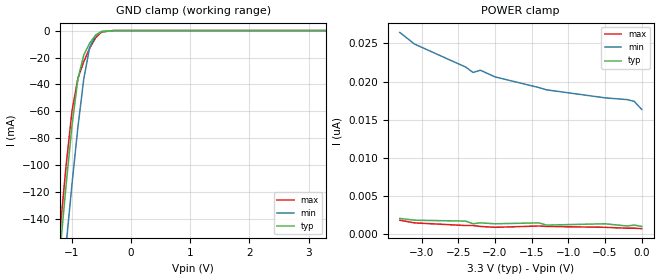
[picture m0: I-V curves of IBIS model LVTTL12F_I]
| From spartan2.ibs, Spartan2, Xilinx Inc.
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|   Model LVTTL12F_I
[Model]   LVTTL12F_I
Model_type   Input
Polarity   Non-Inverting
Vinl =   0.800V
Vinh =   2.000V
C_comp   6.5000pF   5.0000pF   8.0000pF
[Temperature Range]   27.0000   100.0000   0.000
[Voltage Range]   3.3000V   3.0000V   3.6000V
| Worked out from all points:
|   GND clamp passes 1 mA (typ) near -0.51 V on its own axis
[GND_clamp]
| voltage   I(typ)   I(min)   I(max)
-3.3V     -1.286A    -1.273A    -1.29A
-1.3V     -213.2mA   -255.1mA   -198mA
-1.2V     -163mA     -206.8mA   -147.7mA
-1.1V     -114.8mA   -159.6mA   -100.3mA
-1V       -70.57mA   -114.1mA   -59.86mA
-900mV    -35.79mA   -71.75mA   -35.46mA
-800mV    -18.04mA   -35.69mA   -22.98mA
-700mV    -9.256mA   -12.38mA   -13.06mA
-600mV    -3.388mA   -3.468mA   -5.299mA
-500mV    -637.4uA   -792.4uA   -1.07mA
-300mV    -3.973uA   -15.32uA   -4.185uA
3.3V      1.106nA    17.64nA    698.5pA
[POWER_clamp]
| voltage   I(typ)   I(min)   I(max)
-3.3V     2.095nA    26.43nA    1.863nA
-3.1V     1.863nA    24.91nA    1.513nA
-2.4V     1.746nA    21.89nA    1.164nA
-2.3V     1.397nA    21.19nA    1.164nA
-2.2V     1.513nA    21.48nA    1.048nA
-2V       1.397nA    20.61nA    931.3pA
-1.4V     1.513nA    19.21nA    1.106nA
-1.3V     1.222nA    18.92nA    1.048nA
-500mV    1.397nA    17.87nA    931.3pA
-200mV    1.106nA    17.64nA    814.9pA
-100mV    1.222nA    17.4nA     814.9pA
0V        1.048nA    16.36nA    756.7pA
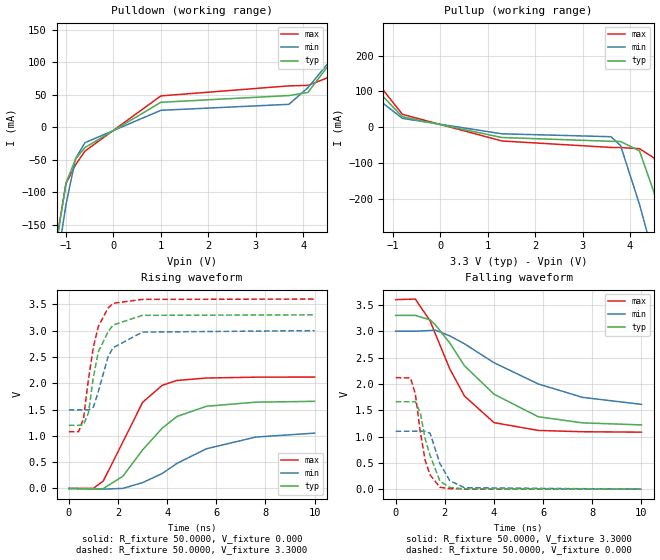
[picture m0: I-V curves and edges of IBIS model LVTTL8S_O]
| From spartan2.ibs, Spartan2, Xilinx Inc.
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|   Model LVTTL8S_O
[Model]   LVTTL8S_O
Model_type   Output
Polarity   Non-Inverting
Vmeas =   1.4000V
Cref =  35.0000pF
Rref =   1.0000M
Vref =  0.000V
C_comp   6.5000pF   5.0000pF   8.0000pF
[Temperature Range]   27.0000   100.0000   0.000
[Voltage Range]   3.3000V   3.0000V   3.6000V
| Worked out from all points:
|   slope of the pulldown table from 0 to 0.495 V, typ, clamps not added: 21.7 ohm
|   slope of the pullup table from 0 to 0.495 V, typ, clamps not added: 37.4 ohm
|   rising waveform, R_fixture 50.0000, V_fixture 0.000: 20-80 % time 1.89ns typ, 2.74ns min, 1.37ns max; typ from 0 V to 1.66 V
|   rising waveform, R_fixture 50.0000, V_fixture 3.3000: 20-80 % time 637ps typ, 679ps min, 554ps max; typ from 1.2 V to 3.3 V
|   falling waveform, R_fixture 50.0000, V_fixture 3.3000: 20-80 % time 2.49ns typ, 3.61ns min, 1.68ns max; typ from 3.3 V to 1.22 V
|   falling waveform, R_fixture 50.0000, V_fixture 0.000: 20-80 % time 547ps typ, 572ps min, 457ps max; typ from 1.66 V to 0 V
[Pulldown]
| voltage   I(typ)   I(min)   I(max)
-3.3V     -1.287A    -1.273A    -1.29A
-1.5V     -319.2mA   -355mA     -306.2mA
-1V       -85.7mA    -119mA     -86.53mA
-800mV    -49.26mA   -48.62mA   -58.07mA
-600mV    -31.33mA   -23.87mA   -36.76mA
1V        38.23mA    25.9mA     48.06mA
3.7V      48.63mA    35.12mA    63.51mA
4.1V      53.36mA    60.68mA    64.22mA
4.5V      91.81mA    96.06mA    75.48mA
4.9V      143.3mA    135.7mA    130.9mA
5.1V      170.4mA    156.5mA    163.1mA
6.6V      374.6mA    313mA      411.1mA
[Pullup]
| voltage   I(typ)   I(min)   I(max)
-3.3V     377.1mA    289.5mA    456.1mA
-2.5V     265.1mA    201.1mA    320.9mA
-800mV    29.02mA    24.47mA    35.82mA
1.3V      -28.95mA   -18.62mA   -38.67mA
3.6V      -39.57mA   -26.75mA   -56.67mA
3.8V      -40.09mA   -51.43mA   -57.06mA
4.2V      -66.46mA   -216mA     -60.14mA
4.5V      -180.3mA   -362.2mA   -85.65mA
4.7V      -279.8mA   -462.2mA   -132.6mA
4.9V      -383.6mA   -563.2mA   -223.6mA
5.1V      -489.4mA   -665mA     -325.3mA
6.6V      -1.3A      -1.436A    -1.143A
[Ramp]
| variable   typ   min   max
dV/dt_r   0.9936/1.9579n   0.6312/2.7392n   1.2702/1.3857n
dV/dt_f   1.2474/2.5568n   0.8334/3.5562n   1.5102/1.6863n
R_load = 50.0000
[Rising Waveform]
R_fixture = 50.0000
V_fixture = 0.000
| time   V(typ)   V(min)   V(max)
0s        0V         0V         0V
1ns       -12.71mV   -3.826mV   2.356mV
1.4ns     -2.362mV   -12.82mV   141.4mV
2.2ns     233.3mV    2.066mV    883.2mV
3ns       732mV      110.9mV    1.636V
3.8ns     1.147V     284.8mV    1.961V
4.4ns     1.368V     476.9mV    2.052V
5.6ns     1.562V     755.2mV    2.099V
7.6ns     1.64V      976.6mV    2.115V
10ns      1.656V     1.052V     2.117V
[Rising Waveform]
R_fixture = 50.0000
V_fixture = 3.3000
V_fixture_min = 3.0000
V_fixture_max = 3.6000
| time   V(typ)   V(min)   V(max)
0s        1.2V       1.493V     1.079V
400ps     1.2V       1.493V     1.08V
600ps     1.212V     1.493V     1.336V
800ps     1.438V     1.493V     2.078V
1ns       2.116V     1.547V     2.688V
1.2ns     2.596V     1.841V     3.076V
1.6ns     2.979V     2.508V     3.432V
1.8ns     3.106V     2.674V     3.518V
3ns       3.29V      2.972V     3.593V
10ns      3.299V     2.999V     3.599V
[Falling Waveform]
R_fixture = 50.0000
V_fixture = 3.3000
V_fixture_min = 3.0000
V_fixture_max = 3.6000
| time   V(typ)   V(min)   V(max)
0s        3.3V       3V         3.6V
800ps     3.3V       3V         3.611V
1.4ns     3.217V     3.014V     3.196V
1.6ns     3.129V     3.022V     2.966V
2.2ns     2.777V     2.912V     2.286V
2.8ns     2.343V     2.761V     1.768V
4ns       1.804V     2.402V     1.264V
5.8ns     1.376V     1.999V     1.116V
7.6ns     1.26V      1.744V     1.091V
10ns      1.221V     1.611V     1.083V
[Falling Waveform]
R_fixture = 50.0000
V_fixture = 0.000
| time   V(typ)   V(min)   V(max)
0s        1.661V     1.1V       2.118V
600ps     1.661V     1.1V       2.113V
800ps     1.662V     1.101V     1.809V
1ns       1.449V     1.101V     1.092V
1.2ns     955.3mV    1.101V     547.3mV
1.4ns     642.9mV    1.06V      270.2mV
1.8ns     151.3mV    486.3mV    36.26mV
2.2ns     33.33mV    161.3mV    10.3mV
2.8ns     6.159mV    27.53mV    3.684mV
10ns      338.1uV    436.9uV    299.4uV
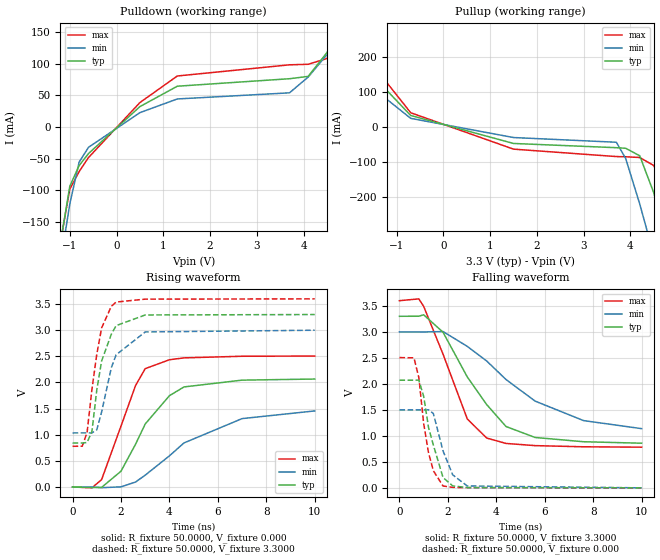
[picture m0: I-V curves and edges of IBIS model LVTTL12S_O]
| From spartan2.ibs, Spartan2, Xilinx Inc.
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|   Model LVTTL12S_O
[Model]   LVTTL12S_O
Model_type   Output
Polarity   Non-Inverting
Vmeas =   1.4000V
Cref =  35.0000pF
Rref =   1.0000M
Vref =  0.000V
C_comp   6.5000pF   5.0000pF   8.0000pF
[Temperature Range]   27.0000   100.0000   0.000
[Voltage Range]   3.3000V   3.0000V   3.6000V
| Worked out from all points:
|   slope of the pulldown table from 0 to 0.495 V, typ, clamps not added: 15.4 ohm
|   slope of the pullup table from 0 to 0.495 V, typ, clamps not added: 25.2 ohm
|   rising waveform, R_fixture 50.0000, V_fixture 0.000: 20-80 % time 1.65ns typ, 2.77ns min, 1.11ns max; typ from 0 V to 2.06 V
|   rising waveform, R_fixture 50.0000, V_fixture 3.3000: 20-80 % time 638ps typ, 706ps min, 524ps max; typ from 0.84 V to 3.3 V
|   falling waveform, R_fixture 50.0000, V_fixture 3.3000: 20-80 % time 2.01ns typ, 3.32ns min, 1.31ns max; typ from 3.3 V to 0.859 V
|   falling waveform, R_fixture 50.0000, V_fixture 0.000: 20-80 % time 589ps typ, 618ps min, 473ps max; typ from 2.07 V to 0 V
[Pulldown]
| voltage   I(typ)   I(min)   I(max)
-3.3V     -1.281A    -1.27A     -1.284A
-1.5V     -318.9mA   -354.1mA   -306.4mA
-1V       -93.51mA   -121.5mA   -98.08mA
-800mV    -60.84mA   -55.35mA   -70.38mA
-600mV    -41.86mA   -32.01mA   -48.2mA
500mV     32.35mA    22.81mA    38.75mA
1.3V      64.57mA    44.42mA    80.71mA
3.7V      76.41mA    54.11mA    98.37mA
4.1V      80.11mA    79.08mA    99.25mA
4.5V      117.6mA    114.4mA    108.3mA
4.9V      168.6mA    153.8mA    162.6mA
6.6V      399mA      330.4mA    441.4mA
[Pullup]
| voltage   I(typ)   I(min)   I(max)
-3.3V     401.3mA    308.2mA    484mA
-2.9V     344.8mA    263.9mA    415.5mA
-2.5V     286.5mA    217.5mA    345.7mA
-700mV    33.24mA    24.98mA    41.08mA
1.5V      -47.01mA   -30.01mA   -63.27mA
3.7V      -59.11mA   -43.53mA   -84.54mA
3.9V      -60.79mA   -90.24mA   -85.1mA
4.2V      -82.34mA   -220.4mA   -87.26mA
4.5V      -188.3mA   -366.3mA   -110.2mA
4.9V      -390.3mA   -567.2mA   -235.3mA
5.1V      -496mA     -668.9mA   -335.5mA
6.6V      -1.307A    -1.44A     -1.153A
[Ramp]
| variable   typ   min   max
dV/dt_r   1.2390/1.6423n   0.8730/2.7720n   1.5030/1.0990n
dV/dt_f   1.4647/2.0141n   1.1166/3.2951n   1.6905/1.3442n
R_load = 50.0000
[Rising Waveform]
R_fixture = 50.0000
V_fixture = 0.000
| time   V(typ)   V(min)   V(max)
0s        0V         0V         0V
800ps     -11.64mV   901.8uV    -16.88mV
1.2ns     -7.903mV   -14.23mV   141.6mV
2ns       301.5mV    2.076mV    1.165V
2.6ns     817mV      94.13mV    1.94V
3ns       1.205V     226.1mV    2.264V
4ns       1.747V     595.7mV    2.434V
4.6ns     1.914V     842.5mV    2.47V
7ns       2.044V     1.308V     2.501V
10ns      2.065V     1.455V     2.505V
[Rising Waveform]
R_fixture = 50.0000
V_fixture = 3.3000
V_fixture_min = 3.0000
V_fixture_max = 3.6000
| time   V(typ)   V(min)   V(max)
0s        840.3mV    1.034V     778.4mV
400ps     840.8mV    1.034V     779.6mV
600ps     850.7mV    1.034V     1.043V
800ps     1.063V     1.034V     1.867V
1ns       1.853V     1.094V     2.54V
1.2ns     2.411V     1.435V     3.043V
1.6ns     2.922V     2.281V     3.457V
1.8ns     3.087V     2.53V      3.538V
3ns       3.291V     2.966V     3.594V
10ns      3.299V     2.999V     3.599V
[Falling Waveform]
R_fixture = 50.0000
V_fixture = 3.3000
V_fixture_min = 3.0000
V_fixture_max = 3.6000
| time   V(typ)   V(min)   V(max)
0s        3.3V       3V         3.6V
800ps     3.301V     3V         3.635V
1ns       3.329V     2.999V     3.491V
1.8ns     2.993V     3.006V     2.571V
2.8ns     2.135V     2.722V     1.327V
3.6ns     1.603V     2.441V     958.1mV
4.4ns     1.18V      2.084V     854.7mV
5.6ns     969.4mV    1.669V     812.4mV
7.6ns     887.2mV    1.294V     790mV
10ns      858.8mV    1.139V     782.5mV
[Falling Waveform]
R_fixture = 50.0000
V_fixture = 0.000
| time   V(typ)   V(min)   V(max)
0s        2.07V      1.5V       2.506V
600ps     2.07V      1.5V       2.501V
800ps     2.072V     1.5V       2.126V
1ns       1.762V     1.5V       1.24V
1.2ns     1.164V     1.501V     675.7mV
1.4ns     824.4mV    1.431V     329.3mV
1.8ns     198.6mV    710.9mV    36.27mV
2.2ns     37.73mV    249.9mV    9.903mV
2.8ns     6.475mV    36.61mV    3.539mV
10ns      341.4uV    468.3uV    303.9uV
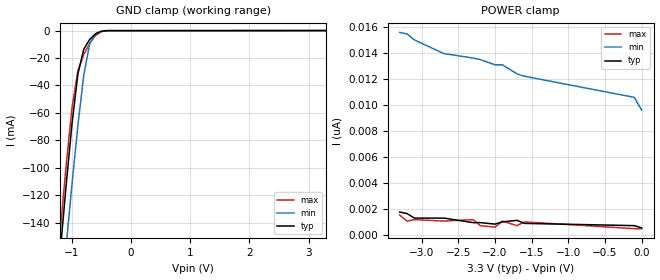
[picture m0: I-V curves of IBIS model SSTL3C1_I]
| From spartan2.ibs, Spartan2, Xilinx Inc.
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|   Model SSTL3C1_I
[Model]   SSTL3C1_I
Model_type   Input
Polarity   Non-Inverting
Vinl =   1.300V
Vinh =   1.700V
C_comp   6.5000pF   5.0000pF   8.0000pF
[Temperature Range]   27.0000   100.0000   0.000
[Voltage Range]   3.3000V   3.0000V   3.6000V
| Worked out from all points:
|   GND clamp passes 1 mA (typ) near -0.53 V on its own axis
[GND_clamp]
| voltage   I(typ)   I(min)   I(max)
-3.3V     -1.286A    -1.272A    -1.289A
-1.2V     -161.8mA   -205.3mA   -146.7mA
-1.1V     -113.2mA   -157.8mA   -98.56mA
-1V       -68.04mA   -112mA     -56.27mA
-900mV    -31.6mA    -69.09mA   -29.2mA
-800mV    -13.5mA    -32.34mA   -17.42mA
-700mV    -6.408mA   -9.455mA   -9.303mA
-600mV    -2.237mA   -2.349mA   -3.538mA
-500mV    -423.5uA   -545.3uA   -698.2uA
-400mV    -42.47uA   -91.26uA   -59.93uA
3.3V      29.92nA    10.77nA    349.2pA
[POWER_clamp]
| voltage   I(typ)   I(min)   I(max)
-3.3V     1.746nA    15.6nA     1.513nA
-3.2V     1.63nA     15.48nA    1.048nA
-3.1V     1.281nA    15.02nA    1.164nA
-2.7V     1.281nA    13.97nA    1.048nA
-2.3V     931.3pA    13.62nA    1.164nA
-2.2V     931.3pA    13.5nA     698.5pA
-2V       814.9pA    13.1nA     582.1pA
-1.9V     989.5pA    13.1nA     1.048nA
-1.7V     1.106nA    12.4nA     698.5pA
-1.6V     873.1pA    12.22nA    989.5pA
-100mV    698.5pA    10.59nA    465.7pA
0V        523.9pA    9.604nA    465.7pA
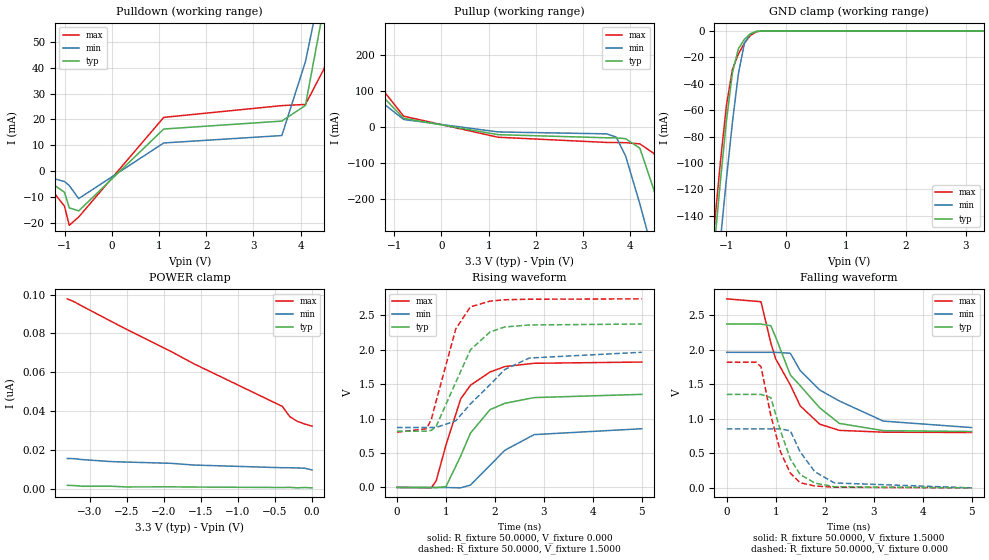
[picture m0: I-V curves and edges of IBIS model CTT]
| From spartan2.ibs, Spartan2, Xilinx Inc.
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|   Model CTT
[Model]   CTT
Model_type   I/O
Polarity   Non-Inverting
Enable   Active-Low
Vinl =   1.300V
Vinh =   1.700V
Vmeas =   1.5000V
Cref =  20.0000pF
Rref =  50.0000
Vref =   1.5000V
C_comp   6.5000pF   5.0000pF   8.0000pF
[Temperature Range]   27.0000   100.0000   0.000
[Voltage Range]   3.3000V   3.0000V   3.6000V
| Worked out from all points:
|   slope of the pulldown table from 0 to 0.495 V, typ, clamps not added: 52.7 ohm
|   slope of the pullup table from 0 to 0.495 V, typ, clamps not added: 48 ohm
|   GND clamp passes 1 mA (typ) near -0.53 V on its own axis
|   rising waveform, R_fixture 50.0000, V_fixture 0.000: 20-80 % time 633ps typ, 847ps min, 568ps max; typ from 0 V to 1.35 V
|   rising waveform, R_fixture 50.0000, V_fixture 1.5000: 20-80 % time 608ps typ, 933ps min, 458ps max; typ from 0.815 V to 2.37 V
|   falling waveform, R_fixture 50.0000, V_fixture 1.5000: 20-80 % time 894ps typ, 1.25ns min, 678ps max; typ from 2.37 V to 0.817 V
|   falling waveform, R_fixture 50.0000, V_fixture 0.000: 20-80 % time 398ps typ, 515ps min, 399ps max; typ from 1.35 V to 0.001 V
[Pulldown]
| voltage   I(typ)   I(min)   I(max)
-3.3V     0A         -1mA       -1mA
-1.5V     -1.8mA     -1.5mA     -1.9mA
-1V       -8.17mA    -4mA       -13.54mA
-900mV    -14.17mA   -5.56mA    -20.93mA
-700mV    -15.35mA   -10.59mA   -17.72mA
1.1V      16.31mA    10.92mA    20.81mA
3.6V      19.37mA    13.78mA    25.36mA
4.1V      25.44mA    42.35mA    25.81mA
4.5V      64.6mA     77.61mA    39.82mA
4.7V      89.71mA    97.03mA    64.96mA
4.9V      116.1mA    117.3mA    95.67mA
6.6V      348mA      295mA      376.7mA
[Pullup]
| voltage   I(typ)   I(min)   I(max)
-3.3V     367mA      281.8mA    444.6mA
-2.7V     284.5mA    216.8mA    344.6mA
-800mV    24.26mA    21.1mA     30.17mA
1.2V      -21.09mA   -13.54mA   -28.27mA
3.5V      -29.77mA   -18.84mA   -42.7mA
3.7V      -29.99mA   -27.95mA   -43mA
3.9V      -32.41mA   -80.94mA   -43.28mA
4.2V      -58.74mA   -213.5mA   -46.66mA
4.5V      -175.5mA   -359.9mA   -73.69mA
4.9V      -379.7mA   -561mA     -216mA
5.1V      -485.7mA   -662.7mA   -318.8mA
6.6V      -1.296A    -1.434A    -1.138A
[GND_clamp]
| voltage   I(typ)   I(min)   I(max)
-3.3V     -1.286A    -1.272A    -1.289A
-1.2V     -161.8mA   -205.3mA   -146.7mA
-1.1V     -113.2mA   -157.8mA   -98.56mA
-1V       -68.04mA   -112mA     -56.27mA
-900mV    -31.6mA    -69.09mA   -29.2mA
-800mV    -13.5mA    -32.34mA   -17.42mA
-700mV    -6.408mA   -9.455mA   -9.303mA
-600mV    -2.237mA   -2.349mA   -3.538mA
-500mV    -423.8uA   -545.3uA   -698.3uA
-400mV    -42.72uA   -91.26uA   -59.96uA
3.3V      295.6nA    10.83nA    27.42nA
[POWER_clamp]
| voltage   I(typ)   I(min)   I(max)
-3.3V     1.746nA    15.6nA     97.79nA
-3.2V     1.63nA     15.48nA    96.16nA
-3.1V     1.281nA    15.02nA    94.06nA
-2.7V     1.281nA    13.97nA    86.03nA
-2.5V     931.3pA    13.74nA    82.07nA
-1.9V     989.5pA    13.1nA     70.66nA
-1.6V     873.1pA    12.22nA    64.49nA
-400mV    640.3pA    10.83nA    42.38nA
-300mV    698.5pA    10.83nA    37.08nA
-200mV    465.7pA    10.71nA    34.75nA
-100mV    640.3pA    10.59nA    33.35nA
0V        465.7pA    9.662nA    32.25nA
[Ramp]
| variable   typ   min   max
dV/dt_r   0.8106/0.6327n   0.5113/0.8454n   1.0920/0.5927n
dV/dt_f   0.5586/0.9428n   0.3726/1.3172n   0.7338/0.7621n
R_load = 50.0000
[Rising Waveform]
R_fixture = 50.0000
V_fixture = 0.000
| time   V(typ)   V(min)   V(max)
0s        8.478uV    0V         0V
700ps     -1.581mV   304.8uV    -4.875mV
800ps     -3.913mV   282.6uV    96.17mV
1ns       12.41mV    -1.627mV   615.9mV
1.3ns     454.4mV    -6.121mV   1.284V
1.5ns     787.9mV    34.02mV    1.483V
1.9ns     1.129V     321.6mV    1.675V
2.2ns     1.22V      538.3mV    1.754V
2.8ns     1.304V     766.7mV    1.802V
5ns       1.351V     852.1mV    1.82V
[Rising Waveform]
R_fixture = 50.0000
V_fixture = 1.5000
V_fixture_min = 1.3500
V_fixture_max = 1.6500
| time   V(typ)   V(min)   V(max)
0s        815.2mV    869.5mV    801.1mV
600ps     817mV      869.7mV    851.9mV
700ps     827.9mV    869.7mV    983.9mV
800ps     887.1mV    869.7mV    1.257V
1.2ns     1.526V     967mV      2.3V
1.5ns     1.998V     1.212V     2.621V
1.9ns     2.256V     1.492V     2.704V
2.2ns     2.329V     1.711V     2.724V
2.7ns     2.358V     1.878V     2.732V
5ns       2.372V     1.962V     2.737V
[Falling Waveform]
R_fixture = 50.0000
V_fixture = 1.5000
V_fixture_min = 1.3500
V_fixture_max = 1.6500
| time   V(typ)   V(min)   V(max)
0s        2.373V     1.964V     2.738V
700ps     2.373V     1.964V     2.697V
900ps     2.349V     1.964V     2.101V
1ns       2.183V     1.964V     1.869V
1.3ns     1.635V     1.95V      1.49V
1.5ns     1.481V     1.7V       1.189V
1.9ns     1.159V     1.418V     922.8mV
2.3ns     934.3mV    1.259V     833.4mV
3.2ns     829.1mV    967.3mV    807.1mV
5ns       816.9mV    873.7mV    802.5mV
[Falling Waveform]
R_fixture = 50.0000
V_fixture = 0.000
| time   V(typ)   V(min)   V(max)
0s        1.354V     854.4mV    1.821V
600ps     1.354V     854.4mV    1.821V
700ps     1.354V     854.4mV    1.755V
900ps     1.308V     854.3mV    1.049V
1.1ns     822.9mV    855.4mV    520.1mV
1.3ns     419.3mV    826.3mV    213.1mV
1.5ns     194.8mV    520.9mV    74.31mV
1.8ns     69.97mV    233.9mV    27.62mV
2.2ns     16.97mV    71.36mV    9.999mV
5ns       864.6uV    743uV      917.8uV
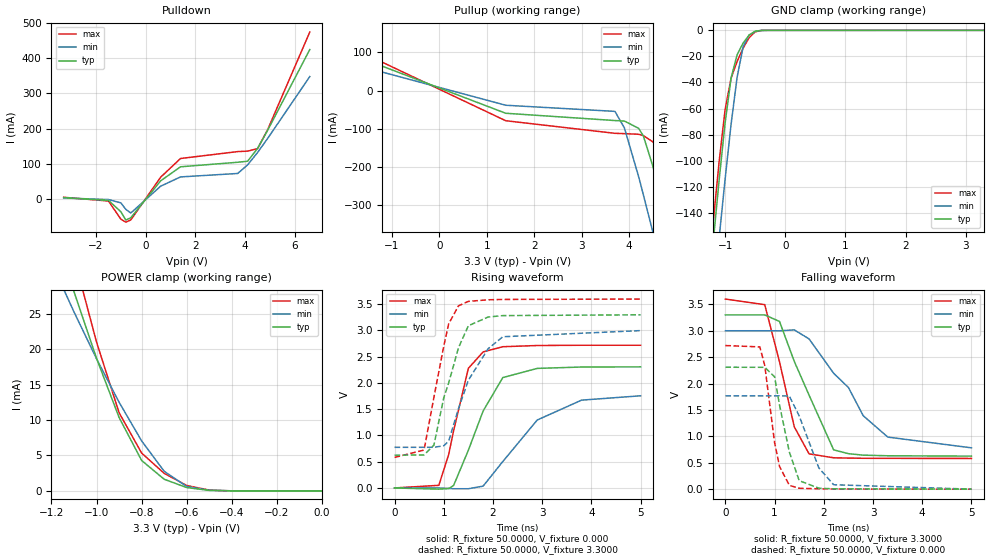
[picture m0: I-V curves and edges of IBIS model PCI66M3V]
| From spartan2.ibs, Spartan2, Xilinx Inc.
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|   Model PCI66M3V
[Model]   PCI66M3V
Model_type   I/O
Polarity   Non-Inverting
Enable   Active-Low
Vinl =   0.900V
Vinh =   1.650V
| Vmeas depends on rising or falling edge, select one of the following:
| For rising edge:
|Vmeas =   0.940V
| For falling edge:
|Vmeas =   2.00V
Cref =  10.0000pF
Rref =  25.0000
| Vref depends on rising or falling edge, select one of the following:
| For rising edge:
|Vref =   0.00V
| For falling edge:
|Vref =   3.30V
C_comp   6.5000pF   5.0000pF   8.0000pF
[Temperature Range]   27.0000   100.0000   0.000
[Voltage Range]   3.3000V   3.0000V   3.6000V
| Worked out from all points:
|   slope of the pulldown table from 0 to 0.495 V, typ, clamps not added: 11.3 ohm
|   slope of the pullup table from 0 to 0.495 V, typ, clamps not added: 19.4 ohm
|   GND clamp passes 1 mA (typ) near -0.51 V on its own axis
|   POWER clamp passes 1 mA (typ) near -0.64 V on its own axis
|   rising waveform, R_fixture 50.0000, V_fixture 0.000: 20-80 % time 614ps typ, 1.01ns min, 393ps max; typ from 0 V to 2.31 V
|   rising waveform, R_fixture 50.0000, V_fixture 3.3000: 20-80 % time 463ps typ, 605ps min, 370ps max; typ from 0.625 V to 3.3 V
|   falling waveform, R_fixture 50.0000, V_fixture 3.3000: 20-80 % time 657ps typ, 1.06ns min, 443ps max; typ from 3.3 V to 0.626 V
|   falling waveform, R_fixture 50.0000, V_fixture 0.000: 20-80 % time 311ps typ, 443ps min, 255ps max; typ from 2.31 V to 0 V
[Pulldown]
| voltage   I(typ)   I(min)   I(max)
-3.3V     4mA        3mA        5mA
-1.5V     -3.8mA     -1.4mA     -5.6mA
-1V       -36.06mA   -10.8mA    -57.22mA
-800mV    -59.59mA   -29.31mA   -65.71mA
-600mV    -53.1mA    -39.63mA   -59.24mA
600mV     51.72mA    36.54mA    62.03mA
1.4V      91.61mA    62.87mA    115.2mA
3.7V      104.5mA    72.65mA    134.8mA
4.1V      107.5mA    97.06mA    136.1mA
4.5V      143.9mA    132.2mA    143.3mA
4.9V      194.6mA    171.6mA    196.4mA
6.6V      424.6mA    347.8mA    474.2mA
[Pullup]
| voltage   I(typ)   I(min)   I(max)
-3.3V     147.4mA    124.4mA    163.8mA
-1.5V     78.26mA    58.57mA    92.03mA
1.4V      -59.13mA   -38.18mA   -78.64mA
3.7V      -78.19mA   -54.2mA    -111.6mA
3.9V      -79.49mA   -97.57mA   -112.4mA
4.2V      -98.59mA   -225.3mA   -114.1mA
4.3V      -118.9mA   -272.8mA   -117.6mA
4.5V      -198.1mA   -370.5mA   -134mA
4.7V      -294.7mA   -470.3mA   -167.8mA
4.9V      -397.4mA   -571.2mA   -249.8mA
5.1V      -502.7mA   -672.9mA   -347.5mA
6.6V      -1.313A    -1.445A    -1.162A
[GND_clamp]
| voltage   I(typ)   I(min)   I(max)
-3.3V     -1.286A    -1.273A    -1.289A
-1.2V     -163.3mA   -206.7mA   -148.3mA
-1.1V     -115.2mA   -159.6mA   -101mA
-1V       -71.04mA   -114.2mA   -60.78mA
-900mV    -36.42mA   -71.86mA   -36.53mA
-800mV    -18.72mA   -35.86mA   -23.84mA
-700mV    -9.715mA   -12.62mA   -13.63mA
-600mV    -3.608mA   -3.649mA   -5.602mA
-500mV    -692.7uA   -854.2uA   -1.156mA
-400mV    -68.48uA   -138.7uA   -98.54uA
-300mV    -4.365uA   -16.73uA   -4.626uA
3.3V      1.106nA    1.475uA    37.54nA
[POWER_clamp]
| voltage   I(typ)   I(min)   I(max)
-3.3V     276.4mA    201.2mA    346.2mA
-1.2V     38.21mA    32.25mA    46.01mA
-1.1V     28.13mA    25.27mA    33mA
-1V       18.72mA    18.66mA    21.02mA
-900mV    10.37mA    12.52mA    11.04mA
-800mV    4.3mA      7.057mA    5.343mA
-700mV    1.647mA    2.774mA    2.48mA
-600mV    473.1uA    621.1uA    767.7uA
-500mV    71.72uA    106uA      114.9uA
-400mV    5.96uA     14.29uA    7.91uA
0V        1.106nA    16.88nA    756.7pA
[Ramp]
| variable   typ   min   max
dV/dt_r   1.3842/0.5892n   1.0536/0.9837n   1.6314/0.4116n
dV/dt_f   1.6045/0.6538n   1.3302/1.0576n   1.8107/0.4642n
R_load = 50.0000
[Rising Waveform]
R_fixture = 50.0000
V_fixture = 0.000
| time   V(typ)   V(min)   V(max)
0s        0V         0V         0V
900ps     -23.32mV   -820.2uV   49.8mV
1.1ns     -12.15mV   -8.63mV    637mV
1.2ns     46.42mV    -15.6mV    1.089V
1.5ns     718.7mV    -15.43mV   2.279V
1.8ns     1.466V     34.58mV    2.592V
2.2ns     2.103V     503.5mV    2.691V
2.9ns     2.278V     1.295V     2.714V
3.8ns     2.304V     1.673V     2.719V
5ns       2.307V     1.756V     2.719V
[Rising Waveform]
R_fixture = 50.0000
V_fixture = 3.3000
V_fixture_min = 3.0000
V_fixture_max = 3.6000
| time   V(typ)   V(min)   V(max)
0s        625mV      774mV      581.5mV
600ps     628.7mV    774.5mV    722.1mV
800ps     815.5mV    774.5mV    1.727V
1ns       1.718V     803.7mV    2.701V
1.1ns     2.001V     891.7mV    3.127V
1.3ns     2.673V     1.513V     3.47V
1.5ns     3.091V     2.052V     3.555V
1.9ns     3.256V     2.651V     3.585V
2.2ns     3.284V     2.881V     3.592V
5ns       3.299V     2.998V     3.599V
[Falling Waveform]
R_fixture = 50.0000
V_fixture = 3.3000
V_fixture_min = 3.0000
V_fixture_max = 3.6000
| time   V(typ)   V(min)   V(max)
0s        3.3V       3V         3.6V
800ps     3.3V       3V         3.494V
1.1ns     3.176V     2.999V     2.412V
1.4ns     2.42V      3.016V     1.181V
1.7ns     1.782V     2.846V     669mV
2.2ns     744.7mV    2.195V     594.4mV
2.5ns     672.6mV    1.926V     589mV
2.8ns     644.5mV    1.392V     585.4mV
3.3ns     632.9mV    986.5mV    583.5mV
5ns       625.9mV    783mV      582.1mV
[Falling Waveform]
R_fixture = 50.0000
V_fixture = 0.000
| time   V(typ)   V(min)   V(max)
0s        2.309V     1.768V     2.72V
700ps     2.308V     1.768V     2.694V
800ps     2.308V     1.768V     2.343V
1ns       2.127V     1.768V     884.1mV
1.1ns     1.594V     1.768V     431.3mV
1.3ns     703.4mV    1.763V     72.39mV
1.5ns     161.6mV    1.388V     17.8mV
1.9ns     18.79mV    401.6mV    7.082mV
2.2ns     7.082mV    84.24mV    3.793mV
5ns       411.1uV    614uV      381.3uV
